VERSION 5.7 ;
  NOWIREEXTENSIONATPIN ON ;
  DIVIDERCHAR "/" ;
  BUSBITCHARS "[]" ;
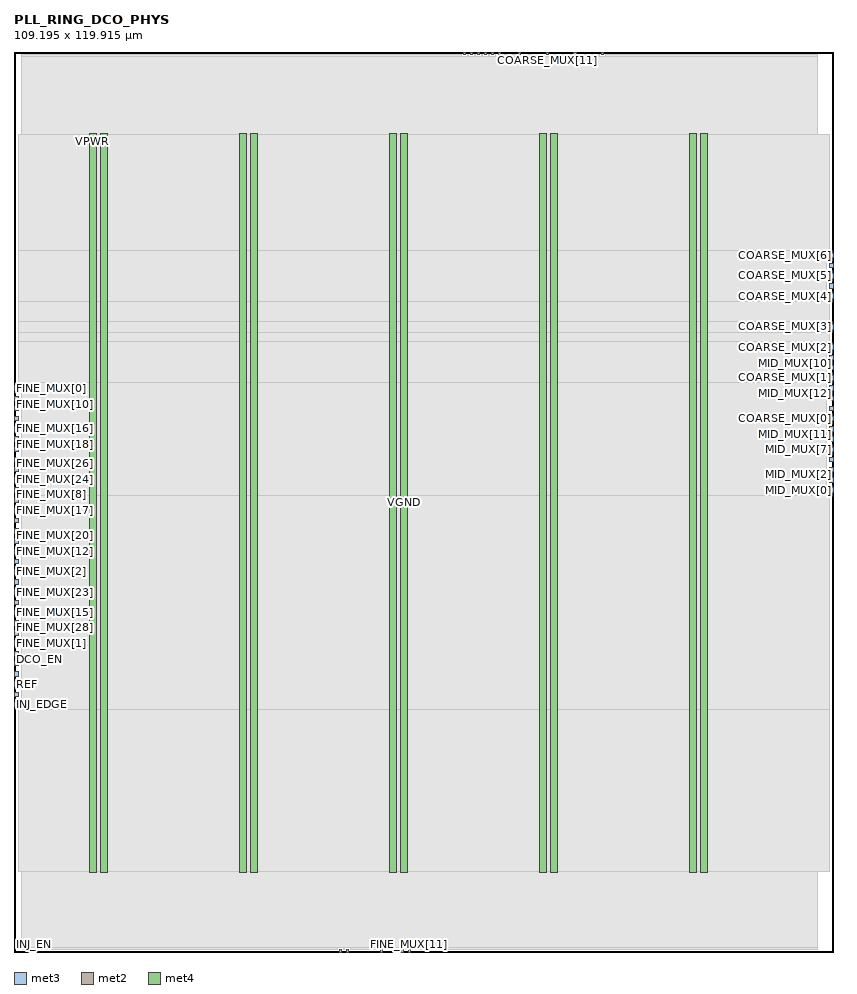
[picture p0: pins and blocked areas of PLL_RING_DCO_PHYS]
MACRO PLL_RING_DCO_PHYS
  CLASS BLOCK ;
  FOREIGN PLL_RING_DCO_PHYS ;
  ORIGIN 0.000 0.000 ;
  SIZE 109.195 BY 119.915 ;
  PIN COARSE_MUX[0]
    DIRECTION INPUT ;
    USE SIGNAL ;
    ANTENNAGATEAREA 0.213000 ;
    PORT
      LAYER met3 ;
        RECT 108.595 70.760 109.195 71.360 ;
    END
  END COARSE_MUX[0]
  PIN COARSE_MUX[10]
    DIRECTION INPUT ;
    USE SIGNAL ;
    ANTENNAGATEAREA 0.213000 ;
    PORT
      LAYER met2 ;
        RECT 74.610 119.635 74.890 119.915 ;
    END
  END COARSE_MUX[10]
  PIN COARSE_MUX[11]
    DIRECTION INPUT ;
    USE SIGNAL ;
    ANTENNAGATEAREA 0.213000 ;
    PORT
      LAYER met2 ;
        RECT 70.930 119.635 71.210 119.915 ;
    END
  END COARSE_MUX[11]
  PIN COARSE_MUX[12]
    DIRECTION INPUT ;
    USE SIGNAL ;
    ANTENNAGATEAREA 0.213000 ;
    PORT
      LAYER met2 ;
        RECT 67.250 119.635 67.530 119.915 ;
    END
  END COARSE_MUX[12]
  PIN COARSE_MUX[13]
    DIRECTION INPUT ;
    USE SIGNAL ;
    ANTENNAGATEAREA 0.213000 ;
    PORT
      LAYER met2 ;
        RECT 64.490 119.635 64.770 119.915 ;
    END
  END COARSE_MUX[13]
  PIN COARSE_MUX[14]
    DIRECTION INPUT ;
    USE SIGNAL ;
    ANTENNAGATEAREA 0.213000 ;
    PORT
      LAYER met2 ;
        RECT 60.810 119.635 61.090 119.915 ;
    END
  END COARSE_MUX[14]
  PIN COARSE_MUX[1]
    DIRECTION INPUT ;
    USE SIGNAL ;
    ANTENNAGATEAREA 0.213000 ;
    PORT
      LAYER met3 ;
        RECT 108.595 76.200 109.195 76.800 ;
    END
  END COARSE_MUX[1]
  PIN COARSE_MUX[2]
    DIRECTION INPUT ;
    USE SIGNAL ;
    ANTENNAGATEAREA 0.213000 ;
    PORT
      LAYER met3 ;
        RECT 108.595 80.280 109.195 80.880 ;
    END
  END COARSE_MUX[2]
  PIN COARSE_MUX[3]
    DIRECTION INPUT ;
    USE SIGNAL ;
    ANTENNAGATEAREA 0.213000 ;
    PORT
      LAYER met3 ;
        RECT 108.595 83.000 109.195 83.600 ;
    END
  END COARSE_MUX[3]
  PIN COARSE_MUX[4]
    DIRECTION INPUT ;
    USE SIGNAL ;
    ANTENNAGATEAREA 0.213000 ;
    PORT
      LAYER met3 ;
        RECT 108.595 87.080 109.195 87.680 ;
    END
  END COARSE_MUX[4]
  PIN COARSE_MUX[5]
    DIRECTION INPUT ;
    USE SIGNAL ;
    ANTENNAGATEAREA 0.213000 ;
    PORT
      LAYER met3 ;
        RECT 108.595 89.800 109.195 90.400 ;
    END
  END COARSE_MUX[5]
  PIN COARSE_MUX[6]
    DIRECTION INPUT ;
    USE SIGNAL ;
    ANTENNAGATEAREA 0.213000 ;
    PORT
      LAYER met3 ;
        RECT 108.595 92.520 109.195 93.120 ;
    END
  END COARSE_MUX[6]
  PIN COARSE_MUX[7]
    DIRECTION INPUT ;
    USE SIGNAL ;
    ANTENNAGATEAREA 0.213000 ;
    PORT
      LAYER met3 ;
        RECT 108.595 91.160 109.195 91.760 ;
    END
  END COARSE_MUX[7]
  PIN COARSE_MUX[8]
    DIRECTION INPUT ;
    USE SIGNAL ;
    ANTENNAGATEAREA 0.213000 ;
    PORT
      LAYER met3 ;
        RECT 108.595 88.440 109.195 89.040 ;
    END
  END COARSE_MUX[8]
  PIN COARSE_MUX[9]
    DIRECTION INPUT ;
    USE SIGNAL ;
    ANTENNAGATEAREA 0.213000 ;
    PORT
      LAYER met2 ;
        RECT 78.290 119.635 78.570 119.915 ;
    END
  END COARSE_MUX[9]
  PIN DCO_EN
    DIRECTION INPUT ;
    USE SIGNAL ;
    ANTENNAGATEAREA 0.213000 ;
    PORT
      LAYER met3 ;
        RECT 0.000 39.480 0.600 40.080 ;
    END
  END DCO_EN
  PIN FINE_MUX[0]
    DIRECTION INPUT ;
    USE SIGNAL ;
    ANTENNAGATEAREA 0.213000 ;
    PORT
      LAYER met3 ;
        RECT 0.000 74.840 0.600 75.440 ;
    END
  END FINE_MUX[0]
  PIN FINE_MUX[10]
    DIRECTION INPUT ;
    USE SIGNAL ;
    ANTENNAGATEAREA 0.213000 ;
    PORT
      LAYER met3 ;
        RECT 0.000 73.480 0.600 74.080 ;
    END
  END FINE_MUX[10]
  PIN FINE_MUX[11]
    DIRECTION INPUT ;
    USE SIGNAL ;
    ANTENNAGATEAREA 0.213000 ;
    PORT
      LAYER met2 ;
        RECT 52.530 0.000 52.810 0.280 ;
    END
  END FINE_MUX[11]
  PIN FINE_MUX[12]
    DIRECTION INPUT ;
    USE SIGNAL ;
    ANTENNAGATEAREA 0.213000 ;
    PORT
      LAYER met3 ;
        RECT 0.000 53.080 0.600 53.680 ;
    END
  END FINE_MUX[12]
  PIN FINE_MUX[13]
    DIRECTION INPUT ;
    USE SIGNAL ;
    ANTENNAGATEAREA 0.213000 ;
    PORT
      LAYER met2 ;
        RECT 44.250 0.000 44.530 0.280 ;
    END
  END FINE_MUX[13]
  PIN FINE_MUX[14]
    DIRECTION INPUT ;
    USE SIGNAL ;
    ANTENNAGATEAREA 0.213000 ;
    PORT
      LAYER met3 ;
        RECT 0.000 72.120 0.600 72.720 ;
    END
  END FINE_MUX[14]
  PIN FINE_MUX[15]
    DIRECTION INPUT ;
    USE SIGNAL ;
    ANTENNAGATEAREA 0.213000 ;
    PORT
      LAYER met3 ;
        RECT 0.000 44.920 0.600 45.520 ;
    END
  END FINE_MUX[15]
  PIN FINE_MUX[16]
    DIRECTION INPUT ;
    USE SIGNAL ;
    ANTENNAGATEAREA 0.213000 ;
    PORT
      LAYER met3 ;
        RECT 0.000 69.400 0.600 70.000 ;
    END
  END FINE_MUX[16]
  PIN FINE_MUX[17]
    DIRECTION INPUT ;
    USE SIGNAL ;
    ANTENNAGATEAREA 0.213000 ;
    PORT
      LAYER met3 ;
        RECT 0.000 58.520 0.600 59.120 ;
    END
  END FINE_MUX[17]
  PIN FINE_MUX[18]
    DIRECTION INPUT ;
    USE SIGNAL ;
    ANTENNAGATEAREA 0.213000 ;
    PORT
      LAYER met3 ;
        RECT 0.000 68.040 0.600 68.640 ;
    END
  END FINE_MUX[18]
  PIN FINE_MUX[19]
    DIRECTION INPUT ;
    USE SIGNAL ;
    ANTENNAGATEAREA 0.213000 ;
    PORT
      LAYER met3 ;
        RECT 0.000 70.760 0.600 71.360 ;
    END
  END FINE_MUX[19]
  PIN FINE_MUX[1]
    DIRECTION INPUT ;
    USE SIGNAL ;
    ANTENNAGATEAREA 0.213000 ;
    PORT
      LAYER met3 ;
        RECT 0.000 40.840 0.600 41.440 ;
    END
  END FINE_MUX[1]
  PIN FINE_MUX[20]
    DIRECTION INPUT ;
    USE SIGNAL ;
    ANTENNAGATEAREA 0.213000 ;
    PORT
      LAYER met3 ;
        RECT 0.000 54.440 0.600 55.040 ;
    END
  END FINE_MUX[20]
  PIN FINE_MUX[21]
    DIRECTION INPUT ;
    USE SIGNAL ;
    ANTENNAGATEAREA 0.213000 ;
    PORT
      LAYER met3 ;
        RECT 0.000 57.160 0.600 57.760 ;
    END
  END FINE_MUX[21]
  PIN FINE_MUX[22]
    DIRECTION INPUT ;
    USE SIGNAL ;
    ANTENNAGATEAREA 0.213000 ;
    PORT
      LAYER met2 ;
        RECT 43.330 0.000 43.610 0.280 ;
    END
  END FINE_MUX[22]
  PIN FINE_MUX[23]
    DIRECTION INPUT ;
    USE SIGNAL ;
    ANTENNAGATEAREA 0.213000 ;
    PORT
      LAYER met3 ;
        RECT 0.000 47.640 0.600 48.240 ;
    END
  END FINE_MUX[23]
  PIN FINE_MUX[24]
    DIRECTION INPUT ;
    USE SIGNAL ;
    ANTENNAGATEAREA 0.213000 ;
    PORT
      LAYER met3 ;
        RECT 0.000 62.600 0.600 63.200 ;
    END
  END FINE_MUX[24]
  PIN FINE_MUX[25]
    DIRECTION INPUT ;
    USE SIGNAL ;
    ANTENNAGATEAREA 0.213000 ;
    PORT
      LAYER met2 ;
        RECT 51.610 0.000 51.890 0.280 ;
    END
  END FINE_MUX[25]
  PIN FINE_MUX[26]
    DIRECTION INPUT ;
    USE SIGNAL ;
    ANTENNAGATEAREA 0.213000 ;
    PORT
      LAYER met3 ;
        RECT 0.000 63.960 0.600 64.560 ;
    END
  END FINE_MUX[26]
  PIN FINE_MUX[27]
    DIRECTION INPUT ;
    USE SIGNAL ;
    ANTENNAGATEAREA 0.213000 ;
    PORT
      LAYER met2 ;
        RECT 48.850 0.000 49.130 0.280 ;
    END
  END FINE_MUX[27]
  PIN FINE_MUX[28]
    DIRECTION INPUT ;
    USE SIGNAL ;
    ANTENNAGATEAREA 0.213000 ;
    PORT
      LAYER met3 ;
        RECT 0.000 42.200 0.600 42.800 ;
    END
  END FINE_MUX[28]
  PIN FINE_MUX[29]
    DIRECTION INPUT ;
    USE SIGNAL ;
    ANTENNAGATEAREA 0.213000 ;
    PORT
      LAYER met3 ;
        RECT 0.000 65.320 0.600 65.920 ;
    END
  END FINE_MUX[29]
  PIN FINE_MUX[2]
    DIRECTION INPUT ;
    USE SIGNAL ;
    ANTENNAGATEAREA 0.213000 ;
    PORT
      LAYER met3 ;
        RECT 0.000 50.360 0.600 50.960 ;
    END
  END FINE_MUX[2]
  PIN FINE_MUX[30]
    DIRECTION INPUT ;
    USE SIGNAL ;
    ANTENNAGATEAREA 0.213000 ;
    PORT
      LAYER met3 ;
        RECT 0.000 55.800 0.600 56.400 ;
    END
  END FINE_MUX[30]
  PIN FINE_MUX[3]
    DIRECTION INPUT ;
    USE SIGNAL ;
    ANTENNAGATEAREA 0.213000 ;
    PORT
      LAYER met3 ;
        RECT 0.000 43.560 0.600 44.160 ;
    END
  END FINE_MUX[3]
  PIN FINE_MUX[4]
    DIRECTION INPUT ;
    USE SIGNAL ;
    ANTENNAGATEAREA 0.213000 ;
    PORT
      LAYER met3 ;
        RECT 0.000 51.720 0.600 52.320 ;
    END
  END FINE_MUX[4]
  PIN FINE_MUX[5]
    DIRECTION INPUT ;
    USE SIGNAL ;
    ANTENNAGATEAREA 0.213000 ;
    PORT
      LAYER met3 ;
        RECT 0.000 61.240 0.600 61.840 ;
    END
  END FINE_MUX[5]
  PIN FINE_MUX[6]
    DIRECTION INPUT ;
    USE SIGNAL ;
    ANTENNAGATEAREA 0.213000 ;
    PORT
      LAYER met3 ;
        RECT 0.000 46.280 0.600 46.880 ;
    END
  END FINE_MUX[6]
  PIN FINE_MUX[7]
    DIRECTION INPUT ;
    USE SIGNAL ;
    ANTENNAGATEAREA 0.213000 ;
    PORT
      LAYER met3 ;
        RECT 0.000 66.680 0.600 67.280 ;
    END
  END FINE_MUX[7]
  PIN FINE_MUX[8]
    DIRECTION INPUT ;
    USE SIGNAL ;
    ANTENNAGATEAREA 0.213000 ;
    PORT
      LAYER met3 ;
        RECT 0.000 59.880 0.600 60.480 ;
    END
  END FINE_MUX[8]
  PIN FINE_MUX[9]
    DIRECTION INPUT ;
    USE SIGNAL ;
    ANTENNAGATEAREA 0.213000 ;
    PORT
      LAYER met3 ;
        RECT 0.000 49.000 0.600 49.600 ;
    END
  END FINE_MUX[9]
  PIN INJ_EDGE
    DIRECTION OUTPUT ;
    USE SIGNAL ;
    ANTENNADIFFAREA 0.504100 ;
    PORT
      LAYER met3 ;
        RECT 0.000 32.680 0.600 33.280 ;
    END
  END INJ_EDGE
  PIN INJ_EN
    DIRECTION INPUT ;
    USE SIGNAL ;
    PORT
      LAYER met2 ;
        RECT 1.930 0.000 2.210 0.280 ;
    END
  END INJ_EN
  PIN MID_MUX[0]
    DIRECTION INPUT ;
    USE SIGNAL ;
    ANTENNAGATEAREA 0.213000 ;
    PORT
      LAYER met3 ;
        RECT 108.595 61.240 109.195 61.840 ;
    END
  END MID_MUX[0]
  PIN MID_MUX[10]
    DIRECTION INPUT ;
    USE SIGNAL ;
    ANTENNAGATEAREA 0.213000 ;
    PORT
      LAYER met3 ;
        RECT 108.595 78.920 109.195 79.520 ;
    END
  END MID_MUX[10]
  PIN MID_MUX[11]
    DIRECTION INPUT ;
    USE SIGNAL ;
    ANTENNAGATEAREA 0.213000 ;
    PORT
      LAYER met3 ;
        RECT 108.595 69.400 109.195 70.000 ;
    END
  END MID_MUX[11]
  PIN MID_MUX[12]
    DIRECTION INPUT ;
    USE SIGNAL ;
    ANTENNAGATEAREA 0.213000 ;
    PORT
      LAYER met3 ;
        RECT 108.595 74.840 109.195 75.440 ;
    END
  END MID_MUX[12]
  PIN MID_MUX[13]
    DIRECTION INPUT ;
    USE SIGNAL ;
    ANTENNAGATEAREA 0.213000 ;
    PORT
      LAYER met3 ;
        RECT 108.595 65.320 109.195 65.920 ;
    END
  END MID_MUX[13]
  PIN MID_MUX[14]
    DIRECTION INPUT ;
    USE SIGNAL ;
    ANTENNAGATEAREA 0.213000 ;
    PORT
      LAYER met2 ;
        RECT 63.570 119.635 63.850 119.915 ;
    END
  END MID_MUX[14]
  PIN MID_MUX[1]
    DIRECTION INPUT ;
    USE SIGNAL ;
    ANTENNAGATEAREA 0.213000 ;
    PORT
      LAYER met2 ;
        RECT 61.730 119.635 62.010 119.915 ;
    END
  END MID_MUX[1]
  PIN MID_MUX[2]
    DIRECTION INPUT ;
    USE SIGNAL ;
    ANTENNAGATEAREA 0.213000 ;
    PORT
      LAYER met3 ;
        RECT 108.595 62.600 109.195 63.200 ;
    END
  END MID_MUX[2]
  PIN MID_MUX[3]
    DIRECTION INPUT ;
    USE SIGNAL ;
    ANTENNAGATEAREA 0.213000 ;
    PORT
      LAYER met2 ;
        RECT 59.890 119.635 60.170 119.915 ;
    END
  END MID_MUX[3]
  PIN MID_MUX[4]
    DIRECTION INPUT ;
    USE SIGNAL ;
    ANTENNAGATEAREA 0.213000 ;
    PORT
      LAYER met2 ;
        RECT 62.650 119.635 62.930 119.915 ;
    END
  END MID_MUX[4]
  PIN MID_MUX[5]
    DIRECTION INPUT ;
    USE SIGNAL ;
    ANTENNAGATEAREA 0.213000 ;
    PORT
      LAYER met3 ;
        RECT 108.595 68.040 109.195 68.640 ;
    END
  END MID_MUX[5]
  PIN MID_MUX[6]
    DIRECTION INPUT ;
    USE SIGNAL ;
    ANTENNAGATEAREA 0.213000 ;
    PORT
      LAYER met3 ;
        RECT 108.595 72.120 109.195 72.720 ;
    END
  END MID_MUX[6]
  PIN MID_MUX[7]
    DIRECTION INPUT ;
    USE SIGNAL ;
    ANTENNAGATEAREA 0.213000 ;
    PORT
      LAYER met3 ;
        RECT 108.595 66.680 109.195 67.280 ;
    END
  END MID_MUX[7]
  PIN MID_MUX[8]
    DIRECTION INPUT ;
    USE SIGNAL ;
    ANTENNAGATEAREA 0.213000 ;
    PORT
      LAYER met3 ;
        RECT 108.595 73.480 109.195 74.080 ;
    END
  END MID_MUX[8]
  PIN MID_MUX[9]
    DIRECTION INPUT ;
    USE SIGNAL ;
    ANTENNAGATEAREA 0.213000 ;
    PORT
      LAYER met3 ;
        RECT 108.595 77.560 109.195 78.160 ;
    END
  END MID_MUX[9]
  PIN MID_OUT
    DIRECTION OUTPUT ;
    USE SIGNAL ;
    ANTENNADIFFAREA 0.504100 ;
    PORT
      LAYER met3 ;
        RECT 108.595 63.960 109.195 64.560 ;
    END
  END MID_OUT
  PIN OUT
    DIRECTION OUTPUT ;
    USE SIGNAL ;
    ANTENNADIFFAREA 0.504100 ;
    PORT
      LAYER met3 ;
        RECT 0.000 38.120 0.600 38.720 ;
    END
  END OUT
  PIN REF
    DIRECTION INPUT ;
    USE SIGNAL ;
    ANTENNAGATEAREA 1.644000 ;
    PORT
      LAYER met3 ;
        RECT 0.000 35.400 0.600 36.000 ;
    END
  END REF
  PIN SS_BBPD[0]
    DIRECTION OUTPUT ;
    USE SIGNAL ;
    ANTENNADIFFAREA 0.504100 ;
    PORT
      LAYER met3 ;
        RECT 0.000 36.760 0.600 37.360 ;
    END
  END SS_BBPD[0]
  PIN SS_BBPD[1]
    DIRECTION OUTPUT ;
    USE SIGNAL ;
    ANTENNADIFFAREA 0.504100 ;
    PORT
      LAYER met3 ;
        RECT 0.000 34.040 0.600 34.640 ;
    END
  END SS_BBPD[1]
  PIN VGND
    DIRECTION INOUT ;
    USE GROUND ;
    PORT
      LAYER met4 ;
        RECT 11.480 10.640 12.440 109.040 ;
    END
    PORT
      LAYER met4 ;
        RECT 31.480 10.640 32.440 109.040 ;
    END
    PORT
      LAYER met4 ;
        RECT 51.480 10.640 52.440 109.040 ;
    END
    PORT
      LAYER met4 ;
        RECT 71.480 10.640 72.440 109.040 ;
    END
    PORT
      LAYER met4 ;
        RECT 91.480 10.640 92.440 109.040 ;
    END
  END VGND
  PIN VPWR
    DIRECTION INOUT ;
    USE POWER ;
    PORT
      LAYER met4 ;
        RECT 10.040 10.640 11.000 109.040 ;
    END
    PORT
      LAYER met4 ;
        RECT 30.040 10.640 31.000 109.040 ;
    END
    PORT
      LAYER met4 ;
        RECT 50.040 10.640 51.000 109.040 ;
    END
    PORT
      LAYER met4 ;
        RECT 70.040 10.640 71.000 109.040 ;
    END
    PORT
      LAYER met4 ;
        RECT 90.040 10.640 91.000 109.040 ;
    END
  END VPWR
  OBS
      LAYER nwell ;
        RECT 5.330 10.795 103.690 108.885 ;
      LAYER li1 ;
        RECT 5.520 10.795 103.500 108.885 ;
      LAYER met1 ;
        RECT 0.990 10.640 107.110 109.040 ;
      LAYER met2 ;
        RECT 1.010 119.355 59.610 119.635 ;
        RECT 60.450 119.355 60.530 119.635 ;
        RECT 61.370 119.355 61.450 119.635 ;
        RECT 62.290 119.355 62.370 119.635 ;
        RECT 63.210 119.355 63.290 119.635 ;
        RECT 64.130 119.355 64.210 119.635 ;
        RECT 65.050 119.355 66.970 119.635 ;
        RECT 67.810 119.355 70.650 119.635 ;
        RECT 71.490 119.355 74.330 119.635 ;
        RECT 75.170 119.355 78.010 119.635 ;
        RECT 78.850 119.355 107.090 119.635 ;
        RECT 1.010 0.560 107.090 119.355 ;
        RECT 1.010 0.280 1.650 0.560 ;
        RECT 2.490 0.280 43.050 0.560 ;
        RECT 43.890 0.280 43.970 0.560 ;
        RECT 44.810 0.280 48.570 0.560 ;
        RECT 49.410 0.280 51.330 0.560 ;
        RECT 52.170 0.280 52.250 0.560 ;
        RECT 53.090 0.280 107.090 0.560 ;
      LAYER met3 ;
        RECT 0.600 93.520 108.595 108.965 ;
        RECT 0.600 86.680 108.195 93.520 ;
        RECT 0.600 84.000 108.595 86.680 ;
        RECT 0.600 82.600 108.195 84.000 ;
        RECT 0.600 81.280 108.595 82.600 ;
        RECT 0.600 75.840 108.195 81.280 ;
        RECT 1.000 60.840 108.195 75.840 ;
        RECT 1.000 32.280 108.595 60.840 ;
        RECT 0.600 10.715 108.595 32.280 ;
  END
END PLL_RING_DCO_PHYS
END LIBRARY

